VERSION 5.7 ;
  NOWIREEXTENSIONATPIN ON ;
  DIVIDERCHAR "/" ;
  BUSBITCHARS "[]" ;
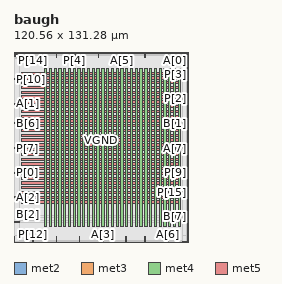
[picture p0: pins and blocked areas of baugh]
MACRO baugh
  CLASS BLOCK ;
  FOREIGN baugh ;
  ORIGIN 0.000 0.000 ;
  SIZE 120.560 BY 131.280 ;
  PIN A[0]
    DIRECTION INPUT ;
    USE SIGNAL ;
    ANTENNAGATEAREA 0.213000 ;
    PORT
      LAYER met2 ;
        RECT 119.230 127.280 119.510 131.280 ;
    END
  END A[0]
  PIN A[1]
    DIRECTION INPUT ;
    USE SIGNAL ;
    ANTENNAGATEAREA 0.213000 ;
    PORT
      LAYER met3 ;
        RECT 0.000 95.240 4.000 95.840 ;
    END
  END A[1]
  PIN A[2]
    DIRECTION INPUT ;
    USE SIGNAL ;
    ANTENNAGATEAREA 0.213000 ;
    PORT
      LAYER met3 ;
        RECT 0.000 30.640 4.000 31.240 ;
    END
  END A[2]
  PIN A[3]
    DIRECTION INPUT ;
    USE SIGNAL ;
    ANTENNAGATEAREA 0.213000 ;
    PORT
      LAYER met2 ;
        RECT 61.270 0.000 61.550 4.000 ;
    END
  END A[3]
  PIN A[4]
    DIRECTION INPUT ;
    USE SIGNAL ;
    ANTENNAGATEAREA 0.159000 ;
    PORT
      LAYER met2 ;
        RECT 29.070 127.280 29.350 131.280 ;
    END
  END A[4]
  PIN A[5]
    DIRECTION INPUT ;
    USE SIGNAL ;
    ANTENNAGATEAREA 0.213000 ;
    PORT
      LAYER met2 ;
        RECT 74.150 127.280 74.430 131.280 ;
    END
  END A[5]
  PIN A[6]
    DIRECTION INPUT ;
    USE SIGNAL ;
    ANTENNAGATEAREA 0.213000 ;
    PORT
      LAYER met2 ;
        RECT 106.350 0.000 106.630 4.000 ;
    END
  END A[6]
  PIN A[7]
    DIRECTION INPUT ;
    USE SIGNAL ;
    ANTENNAGATEAREA 0.495000 ;
    PORT
      LAYER met3 ;
        RECT 116.560 64.640 120.560 65.240 ;
    END
  END A[7]
  PIN B[0]
    DIRECTION INPUT ;
    USE SIGNAL ;
    ANTENNAGATEAREA 0.495000 ;
    PORT
      LAYER met2 ;
        RECT 90.250 0.000 90.530 4.000 ;
    END
  END B[0]
  PIN B[1]
    DIRECTION INPUT ;
    USE SIGNAL ;
    ANTENNAGATEAREA 0.247500 ;
    PORT
      LAYER met3 ;
        RECT 116.560 81.640 120.560 82.240 ;
    END
  END B[1]
  PIN B[2]
    DIRECTION INPUT ;
    USE SIGNAL ;
    ANTENNAGATEAREA 0.159000 ;
    PORT
      LAYER met3 ;
        RECT 0.000 13.640 4.000 14.240 ;
    END
  END B[2]
  PIN B[3]
    DIRECTION INPUT ;
    USE SIGNAL ;
    ANTENNAGATEAREA 0.247500 ;
    PORT
      LAYER met2 ;
        RECT 0.090 0.000 0.370 4.000 ;
    END
  END B[3]
  PIN B[4]
    DIRECTION INPUT ;
    USE SIGNAL ;
    ANTENNAGATEAREA 0.159000 ;
    PORT
      LAYER met2 ;
        RECT 90.250 127.280 90.530 131.280 ;
    END
  END B[4]
  PIN B[5]
    DIRECTION INPUT ;
    USE SIGNAL ;
    ANTENNAGATEAREA 0.213000 ;
    PORT
      LAYER met2 ;
        RECT 106.350 127.280 106.630 131.280 ;
    END
  END B[5]
  PIN B[6]
    DIRECTION INPUT ;
    USE SIGNAL ;
    ANTENNAGATEAREA 0.126000 ;
    PORT
      LAYER met3 ;
        RECT 0.000 81.640 4.000 82.240 ;
    END
  END B[6]
  PIN B[7]
    DIRECTION INPUT ;
    USE SIGNAL ;
    ANTENNAGATEAREA 0.742500 ;
    PORT
      LAYER met3 ;
        RECT 116.560 17.040 120.560 17.640 ;
    END
  END B[7]
  PIN P[0]
    DIRECTION OUTPUT TRISTATE ;
    USE SIGNAL ;
    ANTENNADIFFAREA 0.795200 ;
    PORT
      LAYER met3 ;
        RECT 0.000 47.640 4.000 48.240 ;
    END
  END P[0]
  PIN P[10]
    DIRECTION OUTPUT TRISTATE ;
    USE SIGNAL ;
    ANTENNADIFFAREA 0.795200 ;
    PORT
      LAYER met3 ;
        RECT 0.000 112.240 4.000 112.840 ;
    END
  END P[10]
  PIN P[11]
    DIRECTION OUTPUT TRISTATE ;
    USE SIGNAL ;
    ANTENNADIFFAREA 0.795200 ;
    PORT
      LAYER met3 ;
        RECT 116.560 0.040 120.560 0.640 ;
    END
  END P[11]
  PIN P[12]
    DIRECTION OUTPUT TRISTATE ;
    USE SIGNAL ;
    ANTENNADIFFAREA 0.795200 ;
    PORT
      LAYER met2 ;
        RECT 12.970 0.000 13.250 4.000 ;
    END
  END P[12]
  PIN P[13]
    DIRECTION OUTPUT TRISTATE ;
    USE SIGNAL ;
    ANTENNADIFFAREA 0.795200 ;
    PORT
      LAYER met2 ;
        RECT 29.070 0.000 29.350 4.000 ;
    END
  END P[13]
  PIN P[14]
    DIRECTION OUTPUT TRISTATE ;
    USE SIGNAL ;
    ANTENNADIFFAREA 1.336500 ;
    PORT
      LAYER met2 ;
        RECT 12.970 127.280 13.250 131.280 ;
    END
  END P[14]
  PIN P[15]
    DIRECTION OUTPUT TRISTATE ;
    USE SIGNAL ;
    ANTENNADIFFAREA 0.795200 ;
    PORT
      LAYER met3 ;
        RECT 116.560 34.040 120.560 34.640 ;
    END
  END P[15]
  PIN P[1]
    DIRECTION OUTPUT TRISTATE ;
    USE SIGNAL ;
    ANTENNADIFFAREA 0.795200 ;
    PORT
      LAYER met2 ;
        RECT 45.170 0.000 45.450 4.000 ;
    END
  END P[1]
  PIN P[2]
    DIRECTION OUTPUT TRISTATE ;
    USE SIGNAL ;
    ANTENNADIFFAREA 0.445500 ;
    PORT
      LAYER met3 ;
        RECT 116.560 98.640 120.560 99.240 ;
    END
  END P[2]
  PIN P[3]
    DIRECTION OUTPUT TRISTATE ;
    USE SIGNAL ;
    ANTENNADIFFAREA 0.795200 ;
    PORT
      LAYER met3 ;
        RECT 116.560 115.640 120.560 116.240 ;
    END
  END P[3]
  PIN P[4]
    DIRECTION OUTPUT TRISTATE ;
    USE SIGNAL ;
    ANTENNADIFFAREA 0.795200 ;
    PORT
      LAYER met2 ;
        RECT 41.950 127.280 42.230 131.280 ;
    END
  END P[4]
  PIN P[5]
    DIRECTION OUTPUT TRISTATE ;
    USE SIGNAL ;
    ANTENNADIFFAREA 0.445500 ;
    PORT
      LAYER met2 ;
        RECT 58.050 127.280 58.330 131.280 ;
    END
  END P[5]
  PIN P[6]
    DIRECTION OUTPUT TRISTATE ;
    USE SIGNAL ;
    ANTENNADIFFAREA 0.795200 ;
    PORT
      LAYER met2 ;
        RECT 77.370 0.000 77.650 4.000 ;
    END
  END P[6]
  PIN P[7]
    DIRECTION OUTPUT TRISTATE ;
    USE SIGNAL ;
    ANTENNADIFFAREA 0.795200 ;
    PORT
      LAYER met3 ;
        RECT 0.000 64.640 4.000 65.240 ;
    END
  END P[7]
  PIN P[8]
    DIRECTION OUTPUT TRISTATE ;
    USE SIGNAL ;
    ANTENNADIFFAREA 0.795200 ;
    PORT
      LAYER met3 ;
        RECT 0.000 129.240 4.000 129.840 ;
    END
  END P[8]
  PIN P[9]
    DIRECTION OUTPUT TRISTATE ;
    USE SIGNAL ;
    ANTENNADIFFAREA 0.795200 ;
    PORT
      LAYER met3 ;
        RECT 116.560 47.640 120.560 48.240 ;
    END
  END P[9]
  PIN VGND
    DIRECTION INOUT ;
    USE GROUND ;
    PORT
      LAYER met4 ;
        RECT 24.340 10.640 25.940 119.920 ;
    END
    PORT
      LAYER met4 ;
        RECT 30.940 10.640 32.540 119.920 ;
    END
    PORT
      LAYER met4 ;
        RECT 37.540 10.640 39.140 119.920 ;
    END
    PORT
      LAYER met4 ;
        RECT 44.140 10.640 45.740 119.920 ;
    END
    PORT
      LAYER met4 ;
        RECT 50.740 10.640 52.340 119.920 ;
    END
    PORT
      LAYER met4 ;
        RECT 57.340 10.640 58.940 119.920 ;
    END
    PORT
      LAYER met4 ;
        RECT 63.940 10.640 65.540 119.920 ;
    END
    PORT
      LAYER met4 ;
        RECT 70.540 10.640 72.140 119.920 ;
    END
    PORT
      LAYER met4 ;
        RECT 77.140 10.640 78.740 119.920 ;
    END
    PORT
      LAYER met4 ;
        RECT 83.740 10.640 85.340 119.920 ;
    END
    PORT
      LAYER met4 ;
        RECT 90.340 10.640 91.940 119.920 ;
    END
    PORT
      LAYER met4 ;
        RECT 96.940 10.640 98.540 119.920 ;
    END
    PORT
      LAYER met4 ;
        RECT 103.540 10.640 105.140 119.920 ;
    END
    PORT
      LAYER met4 ;
        RECT 110.140 10.640 111.740 119.920 ;
    END
    PORT
      LAYER met5 ;
        RECT 5.280 30.030 115.240 31.630 ;
    END
    PORT
      LAYER met5 ;
        RECT 5.280 36.630 115.240 38.230 ;
    END
    PORT
      LAYER met5 ;
        RECT 5.280 43.230 115.240 44.830 ;
    END
    PORT
      LAYER met5 ;
        RECT 5.280 49.830 115.240 51.430 ;
    END
    PORT
      LAYER met5 ;
        RECT 5.280 56.430 115.240 58.030 ;
    END
    PORT
      LAYER met5 ;
        RECT 5.280 63.030 115.240 64.630 ;
    END
    PORT
      LAYER met5 ;
        RECT 5.280 69.630 115.240 71.230 ;
    END
    PORT
      LAYER met5 ;
        RECT 5.280 76.230 115.240 77.830 ;
    END
    PORT
      LAYER met5 ;
        RECT 5.280 82.830 115.240 84.430 ;
    END
    PORT
      LAYER met5 ;
        RECT 5.280 89.430 115.240 91.030 ;
    END
    PORT
      LAYER met5 ;
        RECT 5.280 96.030 115.240 97.630 ;
    END
    PORT
      LAYER met5 ;
        RECT 5.280 102.630 115.240 104.230 ;
    END
    PORT
      LAYER met5 ;
        RECT 5.280 109.230 115.240 110.830 ;
    END
    PORT
      LAYER met5 ;
        RECT 5.280 115.830 115.240 117.430 ;
    END
  END VGND
  PIN VPWR
    DIRECTION INOUT ;
    USE POWER ;
    PORT
      LAYER met4 ;
        RECT 21.040 10.640 22.640 119.920 ;
    END
    PORT
      LAYER met4 ;
        RECT 27.640 10.640 29.240 119.920 ;
    END
    PORT
      LAYER met4 ;
        RECT 34.240 10.640 35.840 119.920 ;
    END
    PORT
      LAYER met4 ;
        RECT 40.840 10.640 42.440 119.920 ;
    END
    PORT
      LAYER met4 ;
        RECT 47.440 10.640 49.040 119.920 ;
    END
    PORT
      LAYER met4 ;
        RECT 54.040 10.640 55.640 119.920 ;
    END
    PORT
      LAYER met4 ;
        RECT 60.640 10.640 62.240 119.920 ;
    END
    PORT
      LAYER met4 ;
        RECT 67.240 10.640 68.840 119.920 ;
    END
    PORT
      LAYER met4 ;
        RECT 73.840 10.640 75.440 119.920 ;
    END
    PORT
      LAYER met4 ;
        RECT 80.440 10.640 82.040 119.920 ;
    END
    PORT
      LAYER met4 ;
        RECT 87.040 10.640 88.640 119.920 ;
    END
    PORT
      LAYER met4 ;
        RECT 93.640 10.640 95.240 119.920 ;
    END
    PORT
      LAYER met4 ;
        RECT 100.240 10.640 101.840 119.920 ;
    END
    PORT
      LAYER met4 ;
        RECT 106.840 10.640 108.440 119.920 ;
    END
    PORT
      LAYER met4 ;
        RECT 113.440 10.640 115.040 119.920 ;
    END
    PORT
      LAYER met5 ;
        RECT 5.280 26.730 115.240 28.330 ;
    END
    PORT
      LAYER met5 ;
        RECT 5.280 33.330 115.240 34.930 ;
    END
    PORT
      LAYER met5 ;
        RECT 5.280 39.930 115.240 41.530 ;
    END
    PORT
      LAYER met5 ;
        RECT 5.280 46.530 115.240 48.130 ;
    END
    PORT
      LAYER met5 ;
        RECT 5.280 53.130 115.240 54.730 ;
    END
    PORT
      LAYER met5 ;
        RECT 5.280 59.730 115.240 61.330 ;
    END
    PORT
      LAYER met5 ;
        RECT 5.280 66.330 115.240 67.930 ;
    END
    PORT
      LAYER met5 ;
        RECT 5.280 72.930 115.240 74.530 ;
    END
    PORT
      LAYER met5 ;
        RECT 5.280 79.530 115.240 81.130 ;
    END
    PORT
      LAYER met5 ;
        RECT 5.280 86.130 115.240 87.730 ;
    END
    PORT
      LAYER met5 ;
        RECT 5.280 92.730 115.240 94.330 ;
    END
    PORT
      LAYER met5 ;
        RECT 5.280 99.330 115.240 100.930 ;
    END
    PORT
      LAYER met5 ;
        RECT 5.280 105.930 115.240 107.530 ;
    END
    PORT
      LAYER met5 ;
        RECT 5.280 112.530 115.240 114.130 ;
    END
  END VPWR
  OBS
      LAYER li1 ;
        RECT 5.520 10.795 115.000 119.765 ;
      LAYER met1 ;
        RECT 0.070 10.640 119.530 119.920 ;
      LAYER met2 ;
        RECT 0.100 127.000 12.690 127.685 ;
        RECT 13.530 127.000 28.790 127.685 ;
        RECT 29.630 127.000 41.670 127.685 ;
        RECT 42.510 127.000 57.770 127.685 ;
        RECT 58.610 127.000 73.870 127.685 ;
        RECT 74.710 127.000 89.970 127.685 ;
        RECT 90.810 127.000 106.070 127.685 ;
        RECT 106.910 127.000 118.950 127.685 ;
        RECT 0.100 4.280 119.500 127.000 ;
        RECT 0.650 0.155 12.690 4.280 ;
        RECT 13.530 0.155 28.790 4.280 ;
        RECT 29.630 0.155 44.890 4.280 ;
        RECT 45.730 0.155 60.990 4.280 ;
        RECT 61.830 0.155 77.090 4.280 ;
        RECT 77.930 0.155 89.970 4.280 ;
        RECT 90.810 0.155 106.070 4.280 ;
        RECT 106.910 0.155 119.500 4.280 ;
      LAYER met3 ;
        RECT 4.400 128.840 116.560 129.690 ;
        RECT 3.990 116.640 116.560 128.840 ;
        RECT 3.990 115.240 116.160 116.640 ;
        RECT 3.990 113.240 116.560 115.240 ;
        RECT 4.400 111.840 116.560 113.240 ;
        RECT 3.990 99.640 116.560 111.840 ;
        RECT 3.990 98.240 116.160 99.640 ;
        RECT 3.990 96.240 116.560 98.240 ;
        RECT 4.400 94.840 116.560 96.240 ;
        RECT 3.990 82.640 116.560 94.840 ;
        RECT 4.400 81.240 116.160 82.640 ;
        RECT 3.990 65.640 116.560 81.240 ;
        RECT 4.400 64.240 116.160 65.640 ;
        RECT 3.990 48.640 116.560 64.240 ;
        RECT 4.400 47.240 116.160 48.640 ;
        RECT 3.990 35.040 116.560 47.240 ;
        RECT 3.990 33.640 116.160 35.040 ;
        RECT 3.990 31.640 116.560 33.640 ;
        RECT 4.400 30.240 116.560 31.640 ;
        RECT 3.990 18.040 116.560 30.240 ;
        RECT 3.990 16.640 116.160 18.040 ;
        RECT 3.990 14.640 116.560 16.640 ;
        RECT 4.400 13.240 116.560 14.640 ;
        RECT 3.990 1.040 116.560 13.240 ;
        RECT 3.990 0.175 116.160 1.040 ;
  END
END baugh
END LIBRARY

